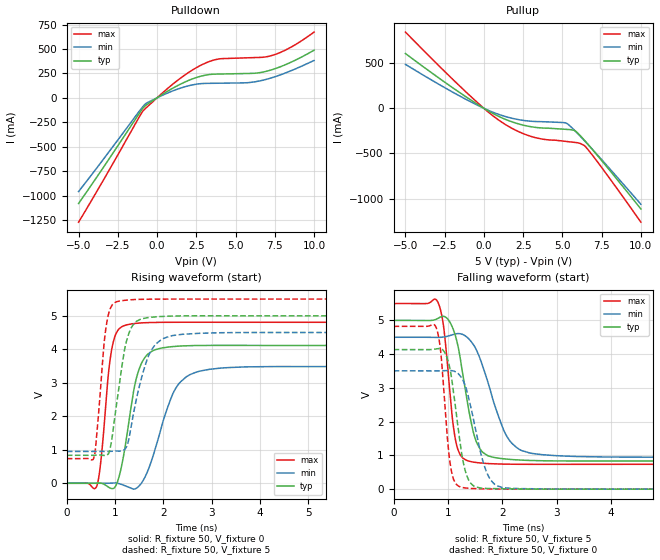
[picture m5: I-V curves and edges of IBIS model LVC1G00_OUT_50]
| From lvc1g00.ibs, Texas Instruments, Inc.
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[Model]   LVC1G00_OUT_50
Model_type  Output
Vref =   0.0
Rref =   500
Cref =   50p
Vmeas =   2.5
| variable   typ   min   max
C_comp   8.59pF   5.67pF   11.16pF
| C_pullup   8.97pF   5.67pF   10.92pF
| C_pulldown   8.20pF   5.98pF   11.16pF
[Temperature Range]   40   100   -40
| Ambient temperature   25   85   -40
[Voltage range]   5   4.5   5.5
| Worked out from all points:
|   slope of the pulldown table from 0 to 0.75 V, typ, clamps not added: 9.97 ohm
|   slope of the pullup table from 0 to 0.75 V, typ, clamps not added: 10.3 ohm
|   rising waveform, R_fixture 50, V_fixture 0: 20-80 % time 296ps typ, 476ps min, 186ps max; typ from 0 V to 4.11 V
|   rising waveform, R_fixture 50, V_fixture 5: 20-80 % time 257ps typ, 360ps min, 167ps max; typ from 0.835 V to 5 V
|   falling waveform, R_fixture 50, V_fixture 5: 20-80 % time 276ps typ, 444ps min, 175ps max; typ from 5 V to 0.835 V
|   falling waveform, R_fixture 50, V_fixture 0: 20-80 % time 214ps typ, 303ps min, 145ps max; typ from 4.13 V to 0 V
[Pulldown]
| LVC1G00_OUT_50
|   Voltage   I(typ)   I(min)   I(max)
-5V       -1.081A    -958.7mA   -1.272A
-930mV    -112.8mA   -95.57mA   -141.9mA
-615mV    -65.29mA   -48.71mA   -90.86mA
1.06V     103.7mA    74.73mA    147.4mA
2.29V     195.8mA    133.5mA    288.4mA
3.355V    239mA      148.3mA    373mA
4.1V      243.6mA    149.9mA    400.8mA
5.83V     249.3mA    155.5mA    409.8mA
6.545V    257.6mA    173.1mA    413.3mA
7.3V      286.7mA    205mA      432.2mA
8.52V     363.3mA    276.1mA    517mA
10V       487.1mA    382.2mA    672.5mA
[Pullup]
| LVC1G00_OUT_50
|   Voltage   I(typ)   I(min)   I(max)
-5V       606.9mA    487.2mA    844.8mA
-1.125V   125.4mA    97.75mA    178.2mA
195mV     -20.35mA   -15.53mA   -29.37mA
1.095V    -101.4mA   -75.91mA   -148.4mA
2.05V     -164.4mA   -119.8mA   -245mA
3.01V     -203.9mA   -143mA     -311.3mA
3.86V     -218.8mA   -148.7mA   -344.2mA
5.285V    -233.1mA   -167.8mA   -367.4mA
5.825V    -250.9mA   -252.6mA   -378.1mA
6.475V    -367.7mA   -371.7mA   -425.3mA
7.675V    -615.1mA   -602.6mA   -696.3mA
10V       -1.115A    -1.063A    -1.261A
[Ramp]
| LVC1G00_OUT_50
| variable   typ   min   max
dV/dt_r   2.56/3.13E-10   2.20/5.10E-10   2.98/1.95E-10
dV/dt_f   2.57/2.86E-10   2.20/4.74E-10   2.94/1.87E-10
R_load = 50
[Rising Waveform]
| LVC1G00_OUT_50
R_fixture =   50
C_fixture =   0
L_fixture =   0
V_fixture =   0
V_fixture_min = 0
V_fixture_max = 0
|   Time   V(typ)   V(min)   V(max)
0s        -145.8nV   2.06uV     -1.656uV
625ps     3.825mV    -88.16uV   -65.12mV
715ps     2.27mV     -171.3uV   795.2mV
880ps     -129.3mV   2.189mV    3.505V
1.005ns   -97.19mV   9.981mV    4.423V
1.13ns    486.7mV    -32.55mV   4.666V
1.535ns   3.549V     -15.45mV   4.787V
2.305ns   4.094V     2.947V     4.808V
3.33ns    4.117V     3.454V     4.808V
50ns      4.114V     3.481V     4.807V
[Rising Waveform]
| LVC1G00_OUT_50
R_fixture =   50
C_fixture =   0
L_fixture =   0
V_fixture =   5
V_fixture_min = 4.5
V_fixture_max = 5.5
|   Time   V(typ)   V(min)   V(max)
0s        835.1mV    949.4mV    736.2mV
565ps     835.8mV    949.4mV    786mV
775ps     831.5mV    949.5mV    4.218V
865ps     883.9mV    950.8mV    5.059V
1.2ns     4.02V      1.012V     5.463V
1.335ns   4.643V     1.713V     5.48V
1.565ns   4.916V     3.243V     5.493V
1.8ns     4.964V     4.08V      5.498V
2.73ns    5.001V     4.477V     5.5V
50ns      5V         4.5V       5.5V
[Falling Waveform]
| LVC1G00_OUT_50
R_fixture =   50
C_fixture =   0
L_fixture =   0
V_fixture =   5
V_fixture_min = 4.5
V_fixture_max = 5.5
|   Time   V(typ)   V(min)   V(max)
0s        5V         4.5V       5.5V
795ps     5.042V     4.495V     5.593V
905ps     5.121V     4.505V     4.982V
1.015ns   5V         4.54V      3.249V
1.215ns   3.985V     4.607V     1.05V
1.475ns   1.641V     4.265V     801.1mV
1.73ns    994.5mV    3.198V     759.4mV
2.255ns   869.4mV    1.247V     737.5mV
3.365ns   833.4mV    967.6mV    735.6mV
50ns      835.1mV    949.4mV    736.2mV
[Falling Waveform]
| LVC1G00_OUT_50
R_fixture =   50
C_fixture =   0
L_fixture =   0
V_fixture =   0
V_fixture_min = 0
V_fixture_max = 0
|   Time   V(typ)   V(min)   V(max)
0s        4.135V     3.505V     4.823V
780ps     4.153V     3.504V     4.798V
865ps     4.161V     3.506V     4.098V
995ps     3.832V     3.514V     1.416V
1.07ns    3.253V     3.51V      487.4mV
1.265ns   938.5mV    3.258V     49.8mV
1.425ns   165.4mV    2.402V     21.94mV
1.745ns   20.39mV    387mV      6.583mV
2.185ns   6.92mV     22.32mV    1.073mV
50ns      1.964uV    5.371uV    46.92nV
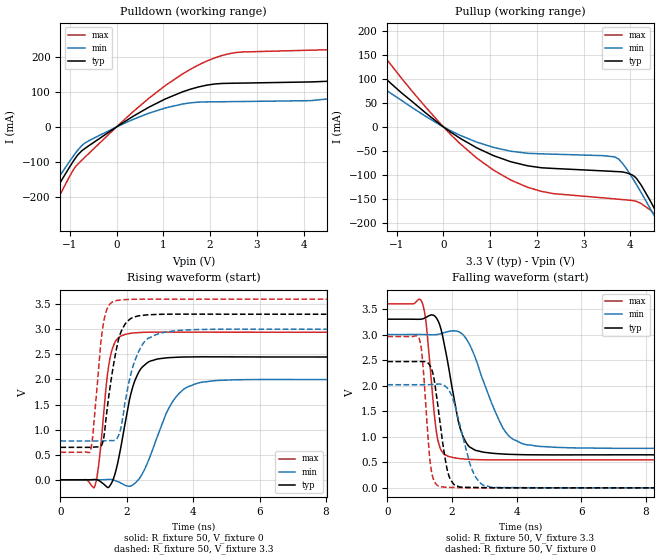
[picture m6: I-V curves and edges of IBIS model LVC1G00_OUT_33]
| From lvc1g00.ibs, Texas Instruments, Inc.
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[Model]   LVC1G00_OUT_33
Model_type  Output
Vref =   0.0
Rref =   500
Cref =   50p
Vmeas =   1.5
| variable   typ   min   max
C_comp   8.48pF   2.80pF   13.16pF
| C_pullup   7.67pF   2.80pF   11.25pF
| C_pulldown   9.29pF   5.73pF   13.16pF
[Temperature Range]   40   100   -40
| Ambient temperature   25   85   -40
[Voltage range]   3.3   3   3.6
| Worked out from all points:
|   slope of the pulldown table from 0 to 0.495 V, typ, clamps not added: 12 ohm
|   slope of the pullup table from 0 to 0.495 V, typ, clamps not added: 15.7 ohm
|   rising waveform, R_fixture 50, V_fixture 0: 20-80 % time 460ps typ, 760ps min, 274ps max; typ from 0 V to 2.45 V
|   rising waveform, R_fixture 50, V_fixture 3.3: 20-80 % time 375ps typ, 484ps min, 255ps max; typ from 0.647 V to 3.3 V
|   falling waveform, R_fixture 50, V_fixture 3.3: 20-80 % time 475ps typ, 820ps min, 267ps max; typ from 3.3 V to 0.647 V
|   falling waveform, R_fixture 50, V_fixture 0: 20-80 % time 328ps typ, 502ps min, 205ps max; typ from 2.47 V to 0 V
[Pulldown]
| LVC1G00_OUT_33
|   Voltage   I(typ)   I(min)   I(max)
-5V       -1.007A    -902.2mA   -1.174A
-2.465V   -446.6mA   -395.8mA   -527.8mA
-1.49V    -223.7mA   -195.8mA   -268.8mA
-565mV    -51.17mA   -37.44mA   -72.18mA
1.045V    80.07mA    54.27mA    118.3mA
2.25V     124.2mA    72mA       203.9mA
4.955V    139mA      90.75mA    224.3mA
6.94V     245.6mA    179.1mA    349.1mA
7.53V     288.8mA    86.31mA    407.3mA
7.915V    302.5mA    81.48mA    448.3mA
8.75V     158mA      82.48mA    511mA
10V       144.3mA    84.07mA    276.2mA
[Pullup]
| LVC1G00_OUT_33
|   Voltage   I(typ)   I(min)   I(max)
-5V       493.1mA    395.6mA    684.5mA
-3.26V    301.9mA    239.3mA    422.7mA
-2.58V    231mA      181.8mA    325mA
-1.85V    158.4mA    123.5mA    224.3mA
-45mV     3.285mA    2.46mA     4.78mA
1.08V     -60.33mA   -43.03mA   -90.81mA
2.1V      -85.39mA   -56.25mA   -134.8mA
3.66V     -93.08mA   -62.51mA   -150.4mA
4.095V    -104.1mA   -114.8mA   -154.6mA
4.63V     -192.2mA   -207.1mA   -202.9mA
4.77V     -218.8mA   -232.4mA   -230.8mA
10V       -1.305A    -1.242A    -1.439A
[Ramp]
| LVC1G00_OUT_33
| variable   typ   min   max
dV/dt_r   1.56/5.05E-10   1.28/8.38E-10   1.86/2.93E-10
dV/dt_f   1.64/5.09E-10   1.38/8.67E-10   1.89/2.82E-10
R_load = 50
[Rising Waveform]
| LVC1G00_OUT_33
R_fixture =   50
C_fixture =   0
L_fixture =   0
V_fixture =   0
V_fixture_min = 0
V_fixture_max = 0
|   Time   V(typ)   V(min)   V(max)
0s        749.1nV    -302.6nV   165.1nV
1.025ns   5.528mV    -84.77uV   -144.6mV
1.15ns    -12.65mV   -291.2uV   283.7mV
1.395ns   -140mV     5.57mV     1.97V
1.535ns   -71.93mV   5.128mV    2.544V
2.215ns   1.924V     -84.6mV    2.927V
2.645ns   2.345V     373mV      2.941V
3.48ns    2.442V     1.649V     2.944V
4.72ns    2.45V      1.98V      2.942V
50ns      2.447V     1.995V     2.942V
[Rising Waveform]
| LVC1G00_OUT_33
R_fixture =   50
C_fixture =   0
L_fixture =   0
V_fixture =   3.3
V_fixture_min = 3
V_fixture_max = 3.6
|   Time   V(typ)   V(min)   V(max)
0s        646.7mV    774.3mV    548mV
895ps     646.7mV    774.3mV    560.2mV
1.245ns   691.9mV    774.7mV    2.89V
1.45ns    1.634V     780.8mV    3.467V
1.71ns    2.677V     830.7mV    3.575V
1.88ns    3.021V     1.246V     3.589V
2.165ns   3.229V     2.214V     3.598V
2.52ns    3.281V     2.742V     3.601V
3.865ns   3.302V     2.988V     3.6V
50ns      3.3V       3V         3.6V
[Falling Waveform]
| LVC1G00_OUT_33
R_fixture =   50
C_fixture =   0
L_fixture =   0
V_fixture =   3.3
V_fixture_min = 3
V_fixture_max = 3.6
|   Time   V(typ)   V(min)   V(max)
0s        3.3V       3V         3.6V
1.08ns    3.303V     3V         3.619V
1.205ns   3.339V     2.998V     3.193V
1.525ns   3.317V     2.999V     1.065V
1.75ns    2.845V     3.034V     664mV
2.3ns     1.073V     3.019V     568.3mV
2.695ns   743.9mV    2.589V     553mV
3.63ns    659.6mV    1.117V     546.3mV
4.72ns    645.7mV    810.9mV    547.4mV
50ns      646.7mV    774.3mV    548mV
[Falling Waveform]
| LVC1G00_OUT_33
R_fixture =   50
C_fixture =   0
L_fixture =   0
V_fixture =   0
V_fixture_min = 0
V_fixture_max = 0
|   Time   V(typ)   V(min)   V(max)
0s        2.471V     2.018V     2.961V
985ps     2.472V     2.018V     2.92V
1.085ns   2.472V     2.017V     2.522V
1.35ns    2.354V     2.02V      386mV
1.68ns    1.037V     2.023V     18.33mV
1.86ns    334.4mV    1.946V     10.81mV
2.065ns   62.21mV    1.669V     6.533mV
2.665ns   8.006mV    291.2mV    622.3uV
3.295ns   1.968mV    6.112mV    -386.7uV
50ns      4.596uV    3.895uV    5.232uV
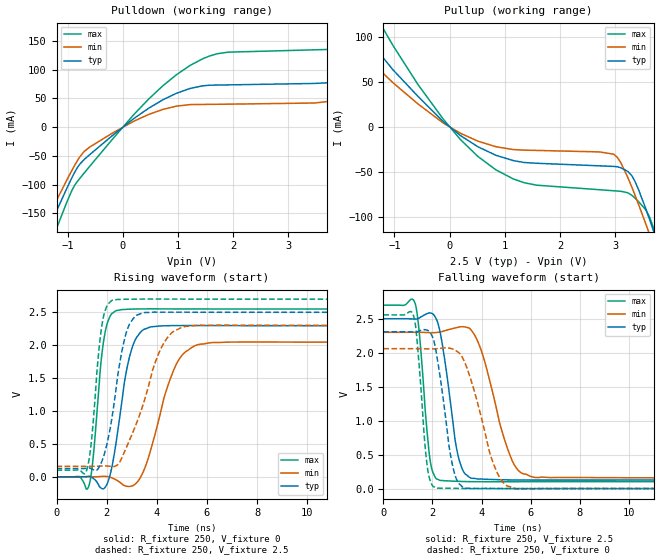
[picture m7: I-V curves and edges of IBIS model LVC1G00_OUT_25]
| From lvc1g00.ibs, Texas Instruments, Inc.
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[Model]   LVC1G00_OUT_25
Model_type  Output
Vref =   0.0
Rref =   500
Cref =   30p
Vmeas =   1.25
| variable   typ   min   max
C_comp   7.78pF   1.19pF   14.38pF
| C_pullup   6.21pF   1.19pF   10.63pF
| C_pulldown   9.35pF   4.55pF   14.38pF
[Temperature Range]   40   100   -40
| Ambient temperature   25   85   -40
[Voltage range]   2.5   2.3   2.7
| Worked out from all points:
|   slope of the pulldown table from 0 to 0.375 V, typ, clamps not added: 13.9 ohm
|   slope of the pullup table from 0 to 0.375 V, typ, clamps not added: 22.2 ohm
|   rising waveform, R_fixture 250, V_fixture 0: 20-80 % time 570ps typ, 932ps min, 355ps max; typ from 0 V to 2.3 V
|   rising waveform, R_fixture 250, V_fixture 2.5: 20-80 % time 601ps typ, 1.13ns min, 352ps max; typ from 0.125 V to 2.5 V
|   falling waveform, R_fixture 250, V_fixture 2.5: 20-80 % time 534ps typ, 935ps min, 347ps max; typ from 2.5 V to 0.125 V
|   falling waveform, R_fixture 250, V_fixture 0: 20-80 % time 527ps typ, 916ps min, 326ps max; typ from 2.31 V to 0 V
[Pulldown]
| LVC1G00_OUT_25
|   Voltage   I(typ)   I(min)   I(max)
-5V       -964.5mA   -872.8mA   -1.115A
-1.565V   -226.1mA   -199.4mA   -269.6mA
-1.175V   -140.9mA   -122.9mA   -170.6mA
-700mV    -56.58mA   -42.46mA   -80.14mA
-200mV    -15.69mA   -11.1mA    -22.59mA
725mV     47.53mA    30.83mA    71.89mA
1.715V    73.33mA    39.84mA    128mA
3.965V    81.26mA    49.43mA    136.9mA
5.285V    134.2mA    90.34mA    197.6mA
5.95V     167mA      44.61mA    249.8mA
6.55V     83.02mA    45.06mA    295.2mA
10V       87.5mA     48.06mA    154.1mA
[Pullup]
| LVC1G00_OUT_25
|   Voltage   I(typ)   I(min)   I(max)
-5V       430mA      345.4mA    594mA
-2.06V    146.2mA    114.5mA    205.5mA
-1.505V   100.3mA    77.7mA     141.8mA
-1.03V    64.19mA    49.74mA    91.44mA
-115mV    6.163mA    4.588mA    8.944mA
840mV     -31.43mA   -21.83mA   -47.7mA
1.58V     -40.31mA   -25.97mA   -64.76mA
2.975V    -43.82mA   -30.23mA   -70.99mA
3.3V      -53.93mA   -66.55mA   -75.91mA
3.625V    -103.1mA   -119.7mA   -100.3mA
3.725V    -121mA     -136.9mA   -117.4mA
10V       -1.408A    -1.338A    -1.542A
[Ramp]
| LVC1G00_OUT_25
| variable   typ   min   max
dV/dt_r   1.49/6.29E-10   1.32/1.02E-09   1.64/3.88E-10
dV/dt_f   1.48/5.82E-10   1.33/1.03E-09   1.61/3.70E-10
R_load = 250
[Rising Waveform]
| LVC1G00_OUT_25
R_fixture =   250
C_fixture =   0
L_fixture =   0
V_fixture =   0
V_fixture_min = 0
V_fixture_max = 0
|   Time   V(typ)   V(min)   V(max)
0s        156.6nV    -502.5nV   287.6nV
1.28ns    7.709mV    -199.1uV   -149.5mV
1.935ns   -161.9mV   6.655mV    2.19V
2.22ns    171.5mV    -18.33mV   2.486V
2.595ns   1.114V     -104.2mV   2.541V
2.945ns   1.873V     -145.8mV   2.548V
3.405ns   2.22V      31.82mV    2.551V
4.775ns   2.299V     1.71V      2.551V
6.11ns    2.298V     2.037V     2.55V
50ns      2.296V     2.045V     2.55V
[Rising Waveform]
| LVC1G00_OUT_25
R_fixture =   250
C_fixture =   0
L_fixture =   0
V_fixture =   2.5
V_fixture_min = 2.3
V_fixture_max = 2.7
|   Time   V(typ)   V(min)   V(max)
0s        125.3mV    158.6mV    101.1mV
1.2ns     129.3mV    158.6mV    96.41mV
1.39ns    122.7mV    158.3mV    536.6mV
1.81ns    236.3mV    163.5mV    2.305V
2.27ns    1.048V     153.9mV    2.688V
2.675ns   2.033V     350.8mV    2.697V
3.07ns    2.41V      700.3mV    2.7V
4.185ns   2.502V     1.966V     2.701V
5.185ns   2.502V     2.288V     2.7V
50ns      2.5V       2.3V       2.7V
[Falling Waveform]
| LVC1G00_OUT_25
R_fixture =   250
C_fixture =   0
L_fixture =   0
V_fixture =   2.5
V_fixture_min = 2.3
V_fixture_max = 2.7
|   Time   V(typ)   V(min)   V(max)
0s        2.5V       2.3V       2.7V
1.3ns     2.495V     2.3V       2.718V
1.47ns    2.512V     2.3V       2.267V
1.89ns    2.586V     2.295V     451.8mV
2.33ns    2.269V     2.306V     118.9mV
3.03ns    507.5mV    2.373V     106.4mV
3.62ns    149.8mV    2.313V     101.5mV
5.265ns   126.8mV    396.1mV    100.6mV
6.17ns    124.7mV    163.7mV    100.9mV
50ns      125.3mV    158.7mV    101.2mV
[Falling Waveform]
| LVC1G00_OUT_25
R_fixture =   250
C_fixture =   0
L_fixture =   0
V_fixture =   0
V_fixture_min = 0
V_fixture_max = 0
|   Time   V(typ)   V(min)   V(max)
0s        2.307V     2.059V     2.557V
1.24ns    2.304V     2.059V     2.53V
1.365ns   2.308V     2.059V     2.21V
1.79ns    2.331V     2.057V     319.4mV
2.19ns    1.927V     2.06V      5.081mV
2.715ns   536.9mV    2.065V     4.372mV
3.04ns    91.58mV    2.009V     2.253mV
4.6ns     1.341mV    264mV      -404.9uV
5.49ns    -174.5uV   -7.494mV   -193.6uV
50ns      11.79uV    19.76uV    7.995uV
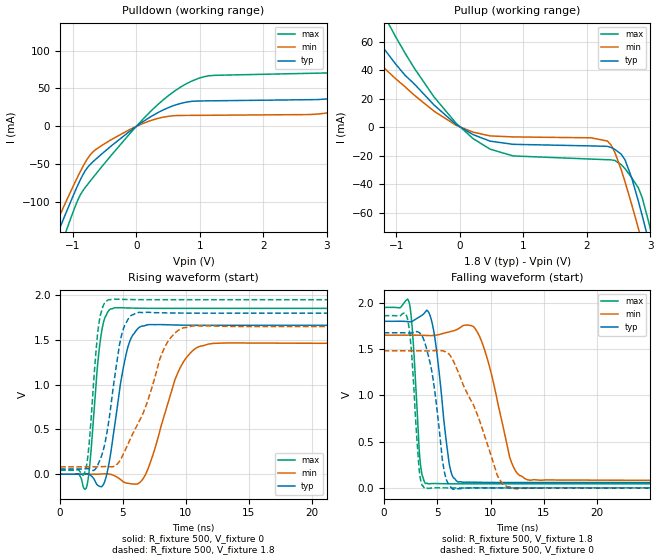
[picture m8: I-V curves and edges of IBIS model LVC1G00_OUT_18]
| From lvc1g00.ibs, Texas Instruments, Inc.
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[Model]   LVC1G00_OUT_18
Model_type  Output
Vref =   0.0
Rref =   1000
Cref =   30p
Vmeas =   0.9
| variable   typ   min   max
C_comp   7.94pF   0.18pF   15.89pF
| C_pullup   4.95pF   0.18pF   8.77pF
| C_pulldown   10.93pF   6.80pF   15.89pF
[Temperature Range]   40   100   -40
| Ambient temperature   25   85   -40
[Voltage range]   1.8   1.65   1.95
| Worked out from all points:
|   slope of the pulldown table from 0 to 0.27 V, typ, clamps not added: 18.2 ohm
|   slope of the pullup table from 0 to 0.27 V, typ, clamps not added: 41 ohm
|   rising waveform, R_fixture 500, V_fixture 0: 20-80 % time 1.11ns typ, 1.93ns min, 666ps max; typ from 0 V to 1.66 V
|   rising waveform, R_fixture 500, V_fixture 1.8: 20-80 % time 1.08ns typ, 2.48ns min, 622ps max; typ from 0.058 V to 1.8 V
|   falling waveform, R_fixture 500, V_fixture 1.8: 20-80 % time 978ps typ, 1.83ns min, 548ps max; typ from 1.8 V to 0.058 V
|   falling waveform, R_fixture 500, V_fixture 0: 20-80 % time 1.1ns typ, 2.99ns min, 620ps max; typ from 1.68 V to 0 V
[Pulldown]
| LVC1G00_OUT_18
|   Voltage   I(typ)   I(min)   I(max)
-5V       -926.2mA   -845.6mA   -1.059A
-1.285V   -150.6mA   -132.2mA   -181mA
-1.13V    -118.6mA   -103.4mA   -143.9mA
-645mV    -43.82mA   -30.94mA   -63.68mA
120mV     7.037mA    4.343mA    10.87mA
790mV     31.99mA    14.4mA     56.3mA
3.325V    41.15mA    22.83mA    73.35mA
4.18V     65.15mA    16.29mA    106.5mA
4.445V    38.68mA    16.42mA    121.1mA
4.7V      37.61mA    16.54mA    131.5mA
5.1V      37.87mA    16.73mA    75.58mA
10V       42.22mA    18.93mA    82.87mA
[Pullup]
| LVC1G00_OUT_18
|   Voltage   I(typ)   I(min)   I(max)
-5V       365.2mA    285.8mA    506.8mA
-1.99V    108.3mA    83.71mA    152.6mA
-1.545V   77.26mA    59.05mA    109.5mA
-1.21V    55.94mA    42.27mA    79.79mA
-60mV     1.854mA    1.297mA    2.751mA
475mV     -9.842mA   -6.169mA   -15.48mA
2.32V     -13.48mA   -9.703mA   -22.88mA
2.6V      -22.99mA   -38.43mA   -29.17mA
2.81V     -52.04mA   -71.15mA   -42.7mA
2.98V     -81.29mA   -99.53mA   -67.98mA
3.15V     -112.1mA   -128.9mA   -100.8mA
10V       -1.513A    -1.437A    -1.648A
[Ramp]
| LVC1G00_OUT_18
| variable   typ   min   max
dV/dt_r   1.09/1.23E-09   0.95/2.18E-09   1.21/7.45E-10
dV/dt_f   1.12/1.11E-09   1.00/2.01E-09   1.20/5.87E-10
R_load = 500
[Rising Waveform]
| LVC1G00_OUT_18
R_fixture =   500
C_fixture =   0
L_fixture =   0
V_fixture =   0
V_fixture_min = 0
V_fixture_max = 0
|   Time   V(typ)   V(min)   V(max)
0s        -478.6nV   -2.21uV    -4.699nV
2.095ns   4.78mV     -133uV     -147.2mV
3.265ns   -139.7mV   2.19mV     1.562V
4.325ns   531.2mV    -16.89mV   1.859V
5.295ns   1.369V     -98.94mV   1.858V
6.14ns    1.622V     -109.1mV   1.855V
7.06ns    1.672V     86.8mV     1.854V
9.56ns    1.666V     1.193V     1.853V
11.77ns   1.664V     1.454V     1.853V
50ns      1.664V     1.463V     1.853V
[Rising Waveform]
| LVC1G00_OUT_18
R_fixture =   500
C_fixture =   0
L_fixture =   0
V_fixture =   1.8
V_fixture_min = 1.65
V_fixture_max = 1.95
|   Time   V(typ)   V(min)   V(max)
0s        57.98mV    82.44mV    43.92mV
2.015ns   61.48mV    82.35mV    44.59mV
2.31ns    58.44mV    82.26mV    347.8mV
3.055ns   123.1mV    83.1mV     1.656V
3.855ns   581mV      84.93mV    1.95V
4.73ns    1.455V     146.2mV    1.955V
5.46ns    1.744V     356.3mV    1.952V
8.29ns    1.803V     1.41V      1.95V
9.81ns    1.8V       1.637V     1.95V
50ns      1.8V       1.65V      1.95V
[Falling Waveform]
| LVC1G00_OUT_18
R_fixture =   500
C_fixture =   0
L_fixture =   0
V_fixture =   1.8
V_fixture_min = 1.65
V_fixture_max = 1.95
|   Time   V(typ)   V(min)   V(max)
0s        1.8V       1.65V      1.95V
2.42ns    1.795V     1.65V      1.986V
3.375ns   1.849V     1.65V      333.1mV
3.935ns   1.906V     1.647V     46.1mV
6.14ns    255.9mV    1.685V     44.11mV
6.95ns    65.07mV    1.717V     43.59mV
8.96ns    60.14mV    1.64V      43.77mV
11.82ns   57.92mV    321.9mV    43.92mV
13.45ns   57.91mV    87.84mV    43.92mV
50ns      57.98mV    82.47mV    43.92mV
[Falling Waveform]
| LVC1G00_OUT_18
R_fixture =   500
C_fixture =   0
L_fixture =   0
V_fixture =   0
V_fixture_min = 0
V_fixture_max = 0
|   Time   V(typ)   V(min)   V(max)
0s        1.675V     1.481V     1.861V
2.235ns   1.673V     1.481V     1.823V
2.615ns   1.675V     1.481V     1.443V
3.315ns   1.679V     1.48V      203.1mV
3.89ns    1.554V     1.48V      -10.86mV
5.65ns    192.6mV    1.477V     166.9uV
6.5ns     -13.75mV   1.375V     -184.4uV
10.63ns   -16.96uV   136.8mV    -2.129uV
12.11ns   -22.07uV   -4.848mV   2.148uV
50ns      4.313uV    13.3uV     1.125uV
